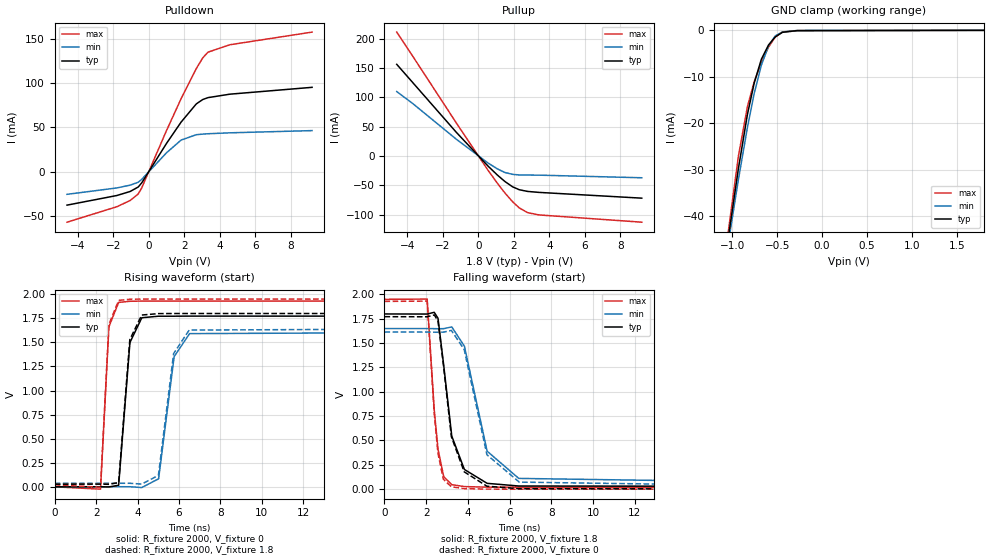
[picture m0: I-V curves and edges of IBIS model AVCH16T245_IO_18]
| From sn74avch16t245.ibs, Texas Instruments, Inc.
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[Model]   AVCH16T245_IO_18
Model_type  I/O
Vinl=0.5775
Vinh=1.2675
Enable   Active-Low
Vref =   0
Rref =   2000
Cref =   15p
Vmeas =   0.9
| variable   typ   min   max
C_comp   5.24pF   4.52pF   5.86pF
| C_pullup   4.77pF   3.53pF   6.89pF
| C_pulldown   4.67pF   4.09pF   5.04pF
| C_tri-state   5.24pF   4.52pF   5.86pF
[Temperature Range]   40   100   -40
| Ambient temperature   25   85   -40
[Voltage range]   1.8   1.65   1.95
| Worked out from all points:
|   slope of the pulldown table from 0 to 0.27 V, typ, clamps not added: 30.8 ohm
|   slope of the pullup table from 0 to 0.27 V, typ, clamps not added: 31.4 ohm
|   GND clamp passes 1 mA (typ) near -0.49 V on its own axis
|   rising waveform, R_fixture 2000, V_fixture 0: 20-80 % time 308ps typ, 485ps min, 208ps max; typ from 0 V to 1.77 V
|   falling waveform, R_fixture 2000, V_fixture 1.8: 20-80 % time 648ps typ, 993ps min, 379ps max; typ from 1.8 V to 0.027 V
|   rising waveform, R_fixture 2000, V_fixture 1.8: 20-80 % time 305ps typ, 476ps min, 207ps max; typ from 0.027 V to 1.8 V
|   falling waveform, R_fixture 2000, V_fixture 0: 20-80 % time 650ps typ, 993ps min, 365ps max; typ from 1.77 V to 0 V
[GND Clamp]
| AVCH16T245_IO_18
|   Voltage   I(typ)   I(min)   I(max)
-4.6V     -599.6mA   -548.2mA   -664.6mA
-1.1V     -52.38mA   -52.81mA   -51.88mA
-1.075V   -48.92mA   -49.68mA   -47.98mA
-930mV    -29.69mA   -32.08mA   -27.04mA
-830mV    -18.1mA    -20.91mA   -16.44mA
-755mV    -11.37mA   -13.59mA   -11.08mA
-675mV    -6.227mA   -7.502mA   -6.966mA
-595mV    -3.153mA   -3.319mA   -3.603mA
-520mV    -1.409mA   -1.191mA   -1.426mA
-440mV    -417.5uA   -333.3uA   -376.2uA
-275mV    -54.37uA   -36.84uA   -89.06uA
1.8V      919.2pA    1.999uA    -415.8nA
[Pulldown]
| AVCH16T245_IO_18
|   Voltage   I(typ)   I(min)   I(max)
-4.6V     -37.94mA   -25.73mA   -57.23mA
-1.8V     -27.09mA   -18.52mA   -39.79mA
-1.045V   -22.5mA    -15.36mA   -32.7mA
-590mV    -17.44mA   -12.06mA   -25.35mA
-395mV    -12.81mA   -8.801mA   -18.52mA
1.005V    31.93mA    21.31mA    46.48mA
1.825V    55.97mA    35.61mA    82.46mA
2.68V     76.51mA    41.68mA    116.5mA
3.045V    81.48mA    42.38mA    128.6mA
3.34V     83.6mA     42.77mA    135mA
4.575V    87.52mA    43.81mA    143.4mA
9.2V      95.24mA    46.32mA    157.7mA
[Pullup]
| AVCH16T245_IO_18
|   Voltage   I(typ)   I(min)   I(max)
-4.6V     156.3mA    109.9mA    211.2mA
-3.695V   125.1mA    89.45mA    169.9mA
-1.245V   40.55mA    28.8mA     56.51mA
535mV     -16.77mA   -11.6mA    -23.84mA
1.065V    -32.16mA   -21.66mA   -46.14mA
1.49V     -43.16mA   -27.88mA   -62.67mA
1.925V    -52.28mA   -31.05mA   -77.72mA
2.305V    -57.27mA   -32.09mA   -88.3mA
2.77V     -60.1mA    -32.26mA   -96.25mA
3.4V      -61.74mA   -32.39mA   -100.1mA
9.2V      -71.58mA   -36.85mA   -112.5mA
[Ramp]
| AVCH16T245_IO_18
| variable   typ   min   max
dV/dt_r   1.08/3.21E-10   0.98/4.99E-10   1.17/2.19E-10
dV/dt_f   1.08/6.54E-10   0.98/1.00E-09   1.17/3.81E-10
R_load = 2000
[Rising Waveform]
| AVCH16T245_IO_18
R_fixture =   2000
C_fixture =   0
L_fixture =   0
V_fixture =   0
V_fixture_min = 0
V_fixture_max = 0
|   Time   V(typ)   V(min)   V(max)
0s        21.35nV    98.25nV    665.6pV
2.21ns    643.3uV    -60.8uV    -24.43mV
2.615ns   -1.201mV   -119uV     1.663V
3.085ns   16.1mV     934.4uV    1.915V
3.63ns    1.499V     847.8uV    1.927V
4.205ns   1.756V     -7.559mV   1.929V
5.015ns   1.772V     83.36mV    1.929V
5.765ns   1.772V     1.352V     1.929V
6.51ns    1.773V     1.591V     1.929V
29.99ns   1.772V     1.614V     1.929V
[Falling Waveform]
| AVCH16T245_IO_18
R_fixture =   2000
C_fixture =   0
L_fixture =   0
V_fixture =   1.8
V_fixture_min = 1.65
V_fixture_max = 1.95
|   Time   V(typ)   V(min)   V(max)
0s        1.8V       1.65V      1.95V
2.045ns   1.799V     1.65V      1.953V
2.385ns   1.817V     1.649V     812.4mV
2.565ns   1.756V     1.648V     410.8mV
2.84ns    1.27V      1.649V     128.5mV
3.225ns   545.2mV    1.667V     46.09mV
3.83ns    202.5mV    1.469V     26.54mV
4.92ns    59.87mV    390.1mV    20.67mV
6.435ns   32.45mV    110.6mV    20.35mV
29.99ns   27.01mV    36.05mV    20.32mV
[Rising Waveform]
| AVCH16T245_IO_18
R_fixture =   2000
C_fixture =   0
L_fixture =   0
V_fixture =   1.8
V_fixture_min = 1.65
V_fixture_max = 1.95
|   Time   V(typ)   V(min)   V(max)
0s        27.01mV    36.05mV    20.32mV
2.21ns    27.66mV    36mV       -3.896mV
2.615ns   25.74mV    35.95mV    1.688V
3.085ns   44.5mV     36.98mV    1.936V
3.625ns   1.529V     36.78mV    1.948V
4.2ns     1.784V     28.57mV    1.95V
5.005ns   1.799V     118.3mV    1.95V
5.74ns    1.8V       1.384V     1.95V
6.49ns    1.8V       1.628V     1.95V
29.99ns   1.8V       1.65V      1.95V
[Falling Waveform]
| AVCH16T245_IO_18
R_fixture =   2000
C_fixture =   0
L_fixture =   0
V_fixture =   0
V_fixture_min = 0
V_fixture_max = 0
|   Time   V(typ)   V(min)   V(max)
0s        1.772V     1.614V     1.929V
2.045ns   1.771V     1.614V     1.932V
2.39ns    1.79V      1.613V     762.4mV
2.565ns   1.727V     1.612V     367.3mV
2.82ns    1.284V     1.613V     102.9mV
3.205ns   539.7mV    1.631V     24.6mV
3.82ns    178.2mV    1.435V     5.445mV
4.91ns    30.39mV    353.5mV    298.1uV
6.46ns    4.689mV    72.43mV    24.38uV
29.99ns   442.3nV    1.165uV    295.9nV
